VERSION 5.7 ;
  NOWIREEXTENSIONATPIN ON ;
  DIVIDERCHAR "/" ;
  BUSBITCHARS "[]" ;
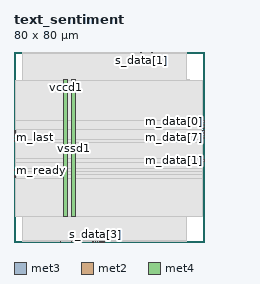
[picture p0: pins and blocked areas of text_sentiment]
MACRO text_sentiment
  CLASS BLOCK ;
  FOREIGN text_sentiment ;
  ORIGIN 0.000 0.000 ;
  SIZE 80.000 BY 80.000 ;
  PIN clk
    DIRECTION INPUT ;
    USE SIGNAL ;
    ANTENNAGATEAREA 1.286700 ;
    ANTENNADIFFAREA 0.434700 ;
    PORT
      LAYER met3 ;
        RECT 0.000 44.920 0.600 45.520 ;
    END
  END clk
  PIN m_data[0]
    DIRECTION OUTPUT ;
    USE SIGNAL ;
    ANTENNADIFFAREA 0.795200 ;
    PORT
      LAYER met3 ;
        RECT 79.400 50.360 80.000 50.960 ;
    END
  END m_data[0]
  PIN m_data[1]
    DIRECTION OUTPUT ;
    USE SIGNAL ;
    ANTENNADIFFAREA 0.795200 ;
    PORT
      LAYER met3 ;
        RECT 79.400 34.040 80.000 34.640 ;
    END
  END m_data[1]
  PIN m_data[2]
    DIRECTION OUTPUT ;
    USE SIGNAL ;
    ANTENNADIFFAREA 0.795200 ;
    PORT
      LAYER met3 ;
        RECT 79.400 44.920 80.000 45.520 ;
    END
  END m_data[2]
  PIN m_data[3]
    DIRECTION OUTPUT ;
    USE SIGNAL ;
    ANTENNADIFFAREA 0.795200 ;
    PORT
      LAYER met3 ;
        RECT 0.000 46.280 0.600 46.880 ;
    END
  END m_data[3]
  PIN m_data[4]
    DIRECTION OUTPUT ;
    USE SIGNAL ;
    ANTENNADIFFAREA 0.795200 ;
    PORT
      LAYER met3 ;
        RECT 79.400 49.000 80.000 49.600 ;
    END
  END m_data[4]
  PIN m_data[5]
    DIRECTION OUTPUT ;
    USE SIGNAL ;
    ANTENNADIFFAREA 0.795200 ;
    PORT
      LAYER met3 ;
        RECT 79.400 46.280 80.000 46.880 ;
    END
  END m_data[5]
  PIN m_data[6]
    DIRECTION OUTPUT ;
    USE SIGNAL ;
    ANTENNADIFFAREA 0.795200 ;
    PORT
      LAYER met3 ;
        RECT 79.400 47.640 80.000 48.240 ;
    END
  END m_data[6]
  PIN m_data[7]
    DIRECTION OUTPUT ;
    USE SIGNAL ;
    ANTENNADIFFAREA 0.795200 ;
    PORT
      LAYER met3 ;
        RECT 79.400 43.560 80.000 44.160 ;
    END
  END m_data[7]
  PIN m_last
    DIRECTION OUTPUT ;
    USE SIGNAL ;
    ANTENNADIFFAREA 0.795200 ;
    PORT
      LAYER met3 ;
        RECT 0.000 43.560 0.600 44.160 ;
    END
  END m_last
  PIN m_ready
    DIRECTION INPUT ;
    USE SIGNAL ;
    ANTENNAGATEAREA 0.647700 ;
    ANTENNADIFFAREA 0.434700 ;
    PORT
      LAYER met3 ;
        RECT 0.000 29.960 0.600 30.560 ;
    END
  END m_ready
  PIN m_valid
    DIRECTION OUTPUT ;
    USE SIGNAL ;
    ANTENNADIFFAREA 0.795200 ;
    PORT
      LAYER met2 ;
        RECT 19.410 0.000 19.690 0.280 ;
    END
  END m_valid
  PIN rst
    DIRECTION INPUT ;
    USE SIGNAL ;
    ANTENNAGATEAREA 0.593700 ;
    ANTENNADIFFAREA 0.434700 ;
    PORT
      LAYER met3 ;
        RECT 0.000 42.200 0.600 42.800 ;
    END
  END rst
  PIN s_data[0]
    DIRECTION INPUT ;
    USE SIGNAL ;
    ANTENNAGATEAREA 0.647700 ;
    ANTENNADIFFAREA 0.434700 ;
    PORT
      LAYER met2 ;
        RECT 58.050 79.720 58.330 80.000 ;
    END
  END s_data[0]
  PIN s_data[1]
    DIRECTION INPUT ;
    USE SIGNAL ;
    ANTENNAGATEAREA 0.647700 ;
    ANTENNADIFFAREA 0.434700 ;
    PORT
      LAYER met2 ;
        RECT 53.450 79.720 53.730 80.000 ;
    END
  END s_data[1]
  PIN s_data[2]
    DIRECTION INPUT ;
    USE SIGNAL ;
    ANTENNAGATEAREA 0.647700 ;
    ANTENNADIFFAREA 0.434700 ;
    PORT
      LAYER met2 ;
        RECT 35.050 0.000 35.330 0.280 ;
    END
  END s_data[2]
  PIN s_data[3]
    DIRECTION INPUT ;
    USE SIGNAL ;
    ANTENNAGATEAREA 0.647700 ;
    ANTENNADIFFAREA 0.434700 ;
    PORT
      LAYER met2 ;
        RECT 34.130 0.000 34.410 0.280 ;
    END
  END s_data[3]
  PIN s_data[4]
    DIRECTION INPUT ;
    USE SIGNAL ;
    ANTENNAGATEAREA 0.647700 ;
    ANTENNADIFFAREA 0.434700 ;
    PORT
      LAYER met2 ;
        RECT 37.810 0.000 38.090 0.280 ;
    END
  END s_data[4]
  PIN s_data[5]
    DIRECTION INPUT ;
    USE SIGNAL ;
    ANTENNAGATEAREA 0.647700 ;
    ANTENNADIFFAREA 0.434700 ;
    PORT
      LAYER met2 ;
        RECT 33.210 0.000 33.490 0.280 ;
    END
  END s_data[5]
  PIN s_data[6]
    DIRECTION INPUT ;
    USE SIGNAL ;
    ANTENNAGATEAREA 0.647700 ;
    ANTENNADIFFAREA 0.434700 ;
    PORT
      LAYER met2 ;
        RECT 36.890 0.000 37.170 0.280 ;
    END
  END s_data[6]
  PIN s_data[7]
    DIRECTION INPUT ;
    USE SIGNAL ;
    ANTENNAGATEAREA 0.647700 ;
    ANTENNADIFFAREA 0.434700 ;
    PORT
      LAYER met2 ;
        RECT 35.970 0.000 36.250 0.280 ;
    END
  END s_data[7]
  PIN s_last
    DIRECTION INPUT ;
    USE SIGNAL ;
    ANTENNAGATEAREA 0.647700 ;
    ANTENNADIFFAREA 0.434700 ;
    PORT
      LAYER met2 ;
        RECT 24.930 0.000 25.210 0.280 ;
    END
  END s_last
  PIN s_ready
    DIRECTION OUTPUT ;
    USE SIGNAL ;
    ANTENNADIFFAREA 0.795200 ;
    PORT
      LAYER met2 ;
        RECT 24.010 0.000 24.290 0.280 ;
    END
  END s_ready
  PIN s_valid
    DIRECTION INPUT ;
    USE SIGNAL ;
    ANTENNAGATEAREA 0.647700 ;
    ANTENNADIFFAREA 0.434700 ;
    PORT
      LAYER met3 ;
        RECT 0.000 27.240 0.600 27.840 ;
    END
  END s_valid
  PIN vccd1
    DIRECTION INOUT ;
    USE POWER ;
    PORT
      LAYER met4 ;
        RECT 21.040 10.640 22.640 68.240 ;
    END
  END vccd1
  PIN vssd1
    DIRECTION INOUT ;
    USE GROUND ;
    PORT
      LAYER met4 ;
        RECT 24.340 10.640 25.940 68.240 ;
    END
  END vssd1
  OBS
      LAYER nwell ;
        RECT 5.330 10.795 74.250 68.190 ;
      LAYER li1 ;
        RECT 5.520 10.795 74.060 68.085 ;
      LAYER met1 ;
        RECT 3.750 10.640 74.060 68.240 ;
      LAYER met2 ;
        RECT 3.770 79.440 53.170 79.720 ;
        RECT 54.010 79.440 57.770 79.720 ;
        RECT 58.610 79.440 72.590 79.720 ;
        RECT 3.770 0.560 72.590 79.440 ;
        RECT 3.770 0.070 19.130 0.560 ;
        RECT 19.970 0.070 23.730 0.560 ;
        RECT 24.570 0.070 24.650 0.560 ;
        RECT 25.490 0.070 32.930 0.560 ;
        RECT 33.770 0.070 33.850 0.560 ;
        RECT 34.690 0.070 34.770 0.560 ;
        RECT 35.610 0.070 35.690 0.560 ;
        RECT 36.530 0.070 36.610 0.560 ;
        RECT 37.450 0.070 37.530 0.560 ;
        RECT 38.370 0.070 72.590 0.560 ;
      LAYER met3 ;
        RECT 0.600 51.360 79.400 68.165 ;
        RECT 0.600 47.280 79.000 51.360 ;
        RECT 1.000 43.160 79.000 47.280 ;
        RECT 1.000 41.800 79.400 43.160 ;
        RECT 0.600 35.040 79.400 41.800 ;
        RECT 0.600 33.640 79.000 35.040 ;
        RECT 0.600 30.960 79.400 33.640 ;
        RECT 1.000 29.560 79.400 30.960 ;
        RECT 0.600 28.240 79.400 29.560 ;
        RECT 1.000 26.840 79.400 28.240 ;
        RECT 0.600 10.715 79.400 26.840 ;
  END
END text_sentiment
END LIBRARY

